VERSION 5.7 ;
BUSBITCHARS "[]" ;
DIVIDERCHAR "/" ;

PROPERTYDEFINITIONS
  MACRO lastSavedExtractCounter INTEGER ;
  LAYER LEF58_TYPE STRING ;
  LAYER LEF58_ENCLOSURE STRING ;
  LAYER LEF58_SPACING STRING ;
  LAYER LEF58_WIDTH STRING ;
END PROPERTYDEFINITIONS

UNITS
  CAPACITANCE PICOFARADS 1 ;
  DATABASE MICRONS 1000 ;
END UNITS
MANUFACTURINGGRID 0.001 ;
LAYER OVERLAP
  TYPE OVERLAP ;
END OVERLAP

# High density, single height
SITE core
  SYMMETRY Y ;
  CLASS CORE ;
  SIZE 0.73 BY 4.04 ;
END core






LAYER PWELL
  TYPE MASTERSLICE ;
  PROPERTY LEF58_TYPE "TYPE PWELL ;" ;
END PWELL

LAYER NWELL
  TYPE MASTERSLICE ;
  PROPERTY LEF58_TYPE "TYPE NWELL ;" ;
  PROPERTY LEF58_SPACING "SPACING 1.4 ;" ;
  PROPERTY LEF58_WIDTH "WIDTH 0.86 ;" ;
END NWELL

LAYER NIMP
  TYPE IMPLANT ;
  WIDTH 0.44 ;
  SPACING 0.44 ;
  AREA 0.3844 ;
END NIMP

LAYER PIMP
  TYPE IMPLANT ;
  WIDTH 0.44 ;
  SPACING 0.44 ;
  AREA 0.3844 ;
END PIMP

LAYER DIFF
  TYPE MASTERSLICE ;
  PROPERTY LEF58_TYPE "TYPE DIFFUSION ;" ;
  PROPERTY LEF58_SPACING "SPACING 0.28 ;" ;
  PROPERTY LEF58_WIDTH "WIDTH 0.22 ;" ;
END DIFF

LAYER POLY1
  TYPE MASTERSLICE ;
END POLY1

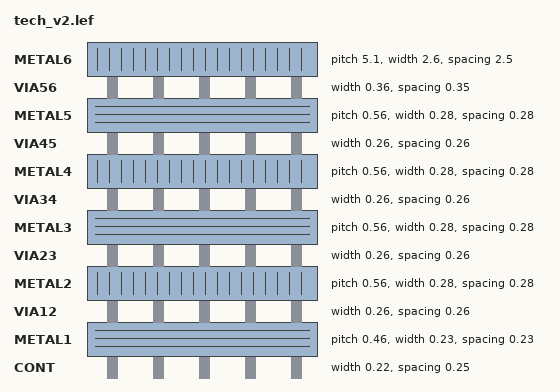
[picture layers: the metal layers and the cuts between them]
LAYER CONT
  TYPE CUT ;
  SPACING 0.25 ;
  SPACING 0.28 ADJACENTCUTS 3 WITHIN 0.3 ;
  WIDTH 0.22 ;
  ENCLOSURE ABOVE 0.005 0.06 ;
  ANTENNAMODEL OXIDE1 ;
    ANTENNAAREARATIO 10 ;
END CONT

LAYER METAL1
  TYPE ROUTING ;
  DIRECTION HORIZONTAL ;
  PITCH 0.46 0.46 ;
  WIDTH 0.23 ;
  OFFSET 0.23 0.23 ;
  AREA 0.202 ;
  SPACINGTABLE
    PARALLELRUNLENGTH 0.004 10.004 
    WIDTH 0.004 0.23 0.23 
    WIDTH 10.004 0.23 0.6 ;
  SPACING 0.23 SAMENET ;
  RESISTANCE RPERSQ 0.078 ;
  MINIMUMDENSITY 30 ;
  ANTENNAMODEL OXIDE1 ;
  ANTENNAAREARATIO 400 ;
END METAL1

LAYER VIA12
  TYPE CUT ;
  SPACING 0.26 ;
  SPACING 0 SAMENET LAYER CONT STACK ;
  SPACING 0 LAYER CONT ;
  WIDTH 0.26 ;
  ENCLOSURE BELOW 0.01 0.06 ;
  ENCLOSURE ABOVE 0.01 0.06 ;
  ANTENNAMODEL OXIDE1 ;
  ANTENNAAREARATIO 20 ;
END VIA12

LAYER METAL2
  TYPE ROUTING ;
  DIRECTION VERTICAL ;
  PITCH 0.56 0.56 ;
  WIDTH 0.28 ;
  OFFSET 0.28 0.28 ;
  AREA 0.202 ;
  SPACINGTABLE
    PARALLELRUNLENGTH 0.004 10.004 
    WIDTH 0.004 0.28 0.28 
    WIDTH 10.004 0.28 0.6 ;
  SPACING 0.28 SAMENET ;
  RESISTANCE RPERSQ 0.078 ;
  MINIMUMDENSITY 30 ;
  ANTENNAMODEL OXIDE1 ;
  ANTENNAAREARATIO 400 ;
END METAL2

LAYER VIA23
  TYPE CUT ;
  SPACING 0.26 ;
  SPACING 0 SAMENET LAYER VIA12 STACK ;
  SPACING 0 LAYER VIA12 ;
  WIDTH 0.26 ;
  ENCLOSURE BELOW 0.01 0.06 ;
  ENCLOSURE ABOVE 0.01 0.06 ;
  ANTENNAMODEL OXIDE1 ;
  ANTENNAAREARATIO 20 ;
END VIA23

LAYER METAL3
  TYPE ROUTING ;
  DIRECTION HORIZONTAL ;
  PITCH 0.56 0.56 ;
  WIDTH 0.28 ;
  OFFSET 0.28 0.28 ;
  AREA 0.202 ;
  SPACINGTABLE
    PARALLELRUNLENGTH 0.004 10.004 
    WIDTH 0.004 0.28 0.28 
    WIDTH 10.004 0.28 0.6 ;
  SPACING 0.28 SAMENET ;
  RESISTANCE RPERSQ 0.078 ;
  MINIMUMDENSITY 30 ;
  ANTENNAMODEL OXIDE1 ;
  ANTENNAAREARATIO 400 ;
END METAL3


LAYER VIA34
  TYPE CUT ;
  SPACING 0.26 ;
  SPACING 0 SAMENET LAYER VIA23 STACK ;
  SPACING 0 LAYER VIA23 ;
  WIDTH 0.26 ;
  ENCLOSURE BELOW 0.01 0.06 ;
  ENCLOSURE ABOVE 0.01 0.06 ;
  ANTENNAMODEL OXIDE1 ;
  ANTENNAAREARATIO 20 ;
END VIA34

LAYER METAL4
  TYPE ROUTING ;
  DIRECTION VERTICAL ;
  PITCH 0.56 0.56 ;
  WIDTH 0.28 ;
  OFFSET 0.28 0.28 ;
  AREA 0.202 ;
  SPACINGTABLE
    PARALLELRUNLENGTH 0.004 10.004 
    WIDTH 0.004 0.28 0.28 
    WIDTH 10.004 0.28 0.6 ;
  SPACING 0.28 SAMENET ;
  RESISTANCE RPERSQ 0.078 ;
  MINIMUMDENSITY 30 ;
  ANTENNAMODEL OXIDE1 ;
  ANTENNAAREARATIO 400 ;
END METAL4

LAYER VIA45
  TYPE CUT ;
  SPACING 0.26 ;
  SPACING 0 SAMENET LAYER VIA34 STACK ;
  SPACING 0 LAYER VIA34 ;
  WIDTH 0.26 ;
  ENCLOSURE BELOW 0.01 0.06 ;
  ENCLOSURE ABOVE 0.01 0.06 ;
  ANTENNAMODEL OXIDE1 ;
  ANTENNAAREARATIO 20 ;
END VIA45

LAYER METAL5
  TYPE ROUTING ;
  DIRECTION HORIZONTAL ;
  PITCH 0.56 0.56 ;
  WIDTH 0.28 ;
  OFFSET 0.28 0.28 ;
  AREA 0.202 ;
  SPACINGTABLE
    PARALLELRUNLENGTH 0.004 10.004 
    WIDTH 0.004 0.28 0.28 
    WIDTH 10.004 0.28 0.6 ;
  SPACING 0.28 SAMENET ;
  RESISTANCE RPERSQ 0.078 ;
  MINIMUMDENSITY 30 ;
  ANTENNAMODEL OXIDE1 ;
  ANTENNAAREARATIO 400 ;
END METAL5


LAYER VIA56
  TYPE CUT ;
  SPACING 0.35 ;
  SPACING 0 SAMENET LAYER VIA45 STACK ;
  SPACING 0 LAYER VIA45 ;
  WIDTH 0.36 ;
  ENCLOSURE BELOW 0.01 0.06 ;
  ENCLOSURE ABOVE 0.4 0.45 ;
  ANTENNAMODEL OXIDE1 ;
  ANTENNAAREARATIO 20 ;
END VIA56

LAYER METAL6
  TYPE ROUTING ;
  DIRECTION VERTICAL ;
  PITCH 5.1 5.1 ;
  WIDTH 2.6 ;
  OFFSET 2.55 2.55 ;
  AREA 6.76 ;
  SPACINGTABLE
    PARALLELRUNLENGTH 0.004 16.004 
    WIDTH 0.004 2.5 2.5 
    WIDTH 16.004 2.5 4 ;
  SPACING 2.5 SAMENET ;
  RESISTANCE RPERSQ 0.0178 ;
  MINIMUMDENSITY 30 ;
  ANTENNAMODEL OXIDE1 ;
  ANTENNAAREARATIO 400 ;
END METAL6


VIARULE M6_M5 GENERATE DEFAULT
  LAYER METAL5 ;
    ENCLOSURE 0.06 0.06 ;
  LAYER METAL6 ;
    ENCLOSURE 0.45 0.45 ;
  LAYER VIA56 ;
    RECT -0.18 -0.18 0.18 0.18 ;
    SPACING 0.71 BY 0.71 ;
END M6_M5

VIARULE M5_M4 GENERATE DEFAULT
  LAYER METAL4 ;
    ENCLOSURE 0.06 0.06 ;
  LAYER METAL5 ;
    ENCLOSURE 0.06 0.06 ;
  LAYER VIA45 ;
    RECT -0.13 -0.13 0.13 0.13 ;
    SPACING 0.52 BY 0.52 ;
END M5_M4

VIARULE M4_M3 GENERATE DEFAULT
  LAYER METAL3 ;
    ENCLOSURE 0.06 0.06 ;
  LAYER METAL4 ;
    ENCLOSURE 0.06 0.06 ;
  LAYER VIA34 ;
    RECT -0.13 -0.13 0.13 0.13 ;
    SPACING 0.52 BY 0.52 ;
END M4_M3

VIARULE M3_M2 GENERATE DEFAULT
  LAYER METAL2 ;
    ENCLOSURE 0.06 0.06 ;
  LAYER METAL3 ;
    ENCLOSURE 0.06 0.06 ;
  LAYER VIA23 ;
    RECT -0.13 -0.13 0.13 0.13 ;
    SPACING 0.52 BY 0.52 ;
END M3_M2

VIARULE M2_M1 GENERATE DEFAULT
  LAYER METAL1 ;
    ENCLOSURE 0.06 0.06 ;
  LAYER METAL2 ;
    ENCLOSURE 0.06 0.06 ;
  LAYER VIA12 ;
    RECT -0.13 -0.13 0.13 0.13 ;
    SPACING 0.52 BY 0.52 ;
END M2_M1

VIARULE M1_PPOLY1 GENERATE
  LAYER POLY1 ;
    ENCLOSURE 0.1 0.1 ;
  LAYER METAL1 ;
    ENCLOSURE 0.06 0.06 ;
  LAYER CONT ;
    RECT -0.11 -0.11 0.11 0.11 ;
    SPACING 0.47 BY 0.47 ;
END M1_PPOLY1

VIARULE M1_NPOLY1 GENERATE
  LAYER POLY1 ;
    ENCLOSURE 0.1 0.1 ;
  LAYER METAL1 ;
    ENCLOSURE 0.06 0.06 ;
  LAYER CONT ;
    RECT -0.11 -0.11 0.11 0.11 ;
    SPACING 0.47 BY 0.47 ;
END M1_NPOLY1

VIARULE M1_POLY1 GENERATE
  LAYER POLY1 ;
    ENCLOSURE 0.1 0.1 ;
  LAYER METAL1 ;
    ENCLOSURE 0.06 0.06 ;
  LAYER CONT ;
    RECT -0.11 -0.11 0.11 0.11 ;
    SPACING 0.47 BY 0.47 ;
END M1_POLY1

VIA M2_M1s
  LAYER VIA12 ;
    RECT -0.13 -0.13 0.13 0.13 ;
  LAYER METAL2 ;
    RECT -0.19 -0.19 0.19 0.19 ;
  LAYER METAL1 ;
    RECT -0.19 -0.19 0.19 0.19 ;
END M2_M1s

VIA M3_M2s
  LAYER VIA23 ;
    RECT -0.13 -0.13 0.13 0.13 ;
  LAYER METAL3 ;
    RECT -0.19 -0.19 0.19 0.19 ;
  LAYER METAL2 ;
    RECT -0.19 -0.19 0.19 0.19 ;
END M3_M2s

VIA M4_M3s
  LAYER VIA34 ;
    RECT -0.13 -0.13 0.13 0.13 ;
  LAYER METAL4 ;
    RECT -0.19 -0.19 0.19 0.19 ;
  LAYER METAL3 ;
    RECT -0.19 -0.19 0.19 0.19 ;
END M4_M3s

VIA M5_M4s
  LAYER VIA45 ;
    RECT -0.13 -0.13 0.13 0.13 ;
  LAYER METAL5 ;
    RECT -0.19 -0.19 0.19 0.19 ;
  LAYER METAL4 ;
    RECT -0.19 -0.19 0.19 0.19 ;
END M5_M4s

VIA M6_M5s
  LAYER VIA56 ;
    RECT -0.18 -0.18 0.18 0.18 ;
  LAYER METAL6 ;
    RECT -0.63 -0.63 0.63 0.63 ;
  LAYER METAL5 ;
    RECT -0.24 -0.24 0.24 0.24 ;
END M6_M5s


